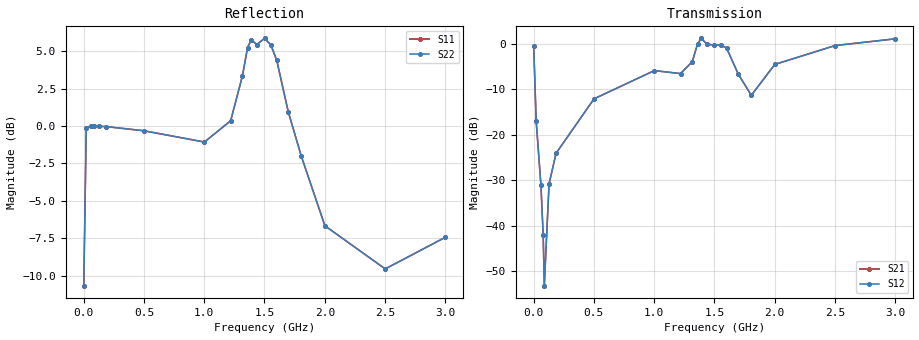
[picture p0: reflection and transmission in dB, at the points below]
!s-Parameter Generated by FASTRON Sdn. Bhd.
!FASTRON P/N : MICC-5R0X
!Keysight Technologies,E4991B,MY54100416,A.01.15
!Date: Fri Aug 28 10:35:03 2026
!Version  : Rev00 Fri Aug 28 10:35:03 2026
!Data & Calibration Information:
!PortZ  Port1:50+j0  Port2:50+j0
!When reading, reference impedance value at option line is always used.
! Remarks : This data is being provided solely for informational purposes.
!Freq	S11	S21	S12	S22
# Hz S dB R 50
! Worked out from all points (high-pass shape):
!   1601 points, 1 MHz to 3 GHz, reference 50 ohm
!   highest |S21| = 1.18 dB at 1.39 GHz (marker M1); lowest = -53.2 dB at 89.1 MHz (marker M2)
!   |S21| within 3 dB of the highest: 1.339 GHz to 1.62 GHz (280.7 MHz wide, 19 % of centre); 2.266 GHz to end of sweep (the widest 2 of 3)
!   lowest |S11| = -10.7 dB at 1 MHz (marker M3), VSWR 1.83, Z = 50.8 + j30.9 ohm
!   |S11| at or under -10 dB: start of sweep to 1.175 MHz
!   |S22| runs from -10.7 to 5.9 dB; largest |S21 - S12| = 0
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1000000  -10.66 71.4  -0.46 -17.0  -0.46 -17.0  -10.66 71.4
2.161812e7  -0.11 8.1  -16.97 -80.9  -16.97 -80.9  -0.11 8.1
6.098e7  -0.02 1.6  -31.08 -84.5  -31.08 -84.5  -0.02 1.6
7.972375e7  -0.02 0.4  -42.03 -74.0  -42.03 -74.0  -0.02 0.4
8.909562e7  -0.02 -0.0  -53.22 16.2  -53.22 16.2  -0.02 -0.0
1.284575e8  -0.02 -1.6  -30.84 84.3  -30.84 84.3  -0.02 -1.6
1.865631e8  -0.04 -3.6  -24.10 84.4  -24.10 84.4  -0.04 -3.6
5.014581e8  -0.32 -14.3  -12.12 74.4  -12.12 74.4  -0.32 -14.3
1.001916e9  -1.07 -30.4  -5.91 62.0  -5.91 62.0  -1.07 -30.4
1.219344e9  0.35 -26.5  -6.57 81.7  -6.57 81.7  0.35 -26.5
1.316811e9  3.34 -20.4  -3.93 126.4  -3.93 126.4  3.34 -20.4
1.359922e9  5.24 -23.3  -0.07 133.3  -0.07 133.3  5.24 -23.3
1.389912e9  5.75 -27.3  1.18 129.1  1.18 129.1  5.75 -27.3
1.436771e9  5.44 -20.1  -0.06 139.7  -0.06 139.7  5.44 -20.1
1.5005e9  5.85 2.5  -0.33 -174.9  -0.33 -174.9  5.85 2.5
1.552982e9  5.41 19.2  -0.21 -141.1  -0.21 -141.1  5.41 19.2
1.601716e9  4.38 27.1  -1.00 -122.1  -1.00 -122.1  4.38 27.1
1.697309e9  0.94 24.7  -6.64 -91.6  -6.64 -91.6  0.94 24.7
1.806023e9  -2.03 11.1  -11.35 -34.3  -11.35 -34.3  -2.03 11.1
2.000958e9  -6.66 -21.5  -4.55 16.7  -4.55 16.7  -6.66 -21.5
2.501416e9  -9.54 -72.7  -0.40 19.5  -0.40 19.5  -9.54 -72.7
3e9  -7.43 -96.9  1.08 21.9  1.08 21.9  -7.43 -96.9
